VERSION 5.8 ;
BUSBITCHARS "[]" ;
DIVIDERCHAR "/" ;
UNITS
    DATABASE MICRONS 1000 ;
END UNITS

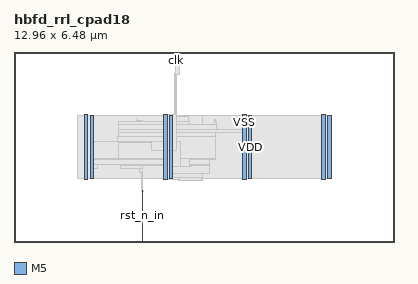
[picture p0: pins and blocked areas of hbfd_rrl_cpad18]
MACRO hbfd_rrl_cpad18
  FOREIGN hbfd_rrl_cpad18 0 0 ;
  CLASS BLOCK ;
  SIZE 12.96 BY 6.48 ;
  PIN clk
    DIRECTION INPUT ;
    USE SIGNAL ;
    PORT
      LAYER M5 ;
        RECT  5.52 6.396 5.544 6.48 ;
    END
  END clk
  PIN rst_n
    DIRECTION OUTPUT ;
    USE SIGNAL ;
    PORT
      LAYER M5 ;
        RECT  5.616 6.396 5.64 6.48 ;
    END
  END rst_n
  PIN rst_n_in
    DIRECTION INPUT ;
    USE SIGNAL ;
    PORT
      LAYER M5 ;
        RECT  4.368 0 4.392 0.084 ;
    END
    PORT
      LAYER M5 ;
        RECT  4.368 0.016 4.392 1.763 ;
    END
  END rst_n_in
  PIN VDD
    DIRECTION INOUT ;
    USE POWER ;
    PORT
      LAYER M5 ;
        RECT  10.692 2.151 10.812 4.329 ;
        RECT  7.992 2.151 8.112 4.329 ;
        RECT  5.292 2.151 5.412 4.329 ;
        RECT  2.592 2.151 2.712 4.329 ;
    END
  END VDD
  PIN VSS
    DIRECTION INOUT ;
    USE GROUND ;
    PORT
      LAYER M5 ;
        RECT  10.5 2.137 10.62 4.343 ;
        RECT  7.8 2.137 7.92 4.343 ;
        RECT  5.1 2.137 5.22 4.343 ;
        RECT  2.4 2.137 2.52 4.343 ;
    END
  END VSS
  # OT_OBS_CLOSED layer=M5 d_um=1.536 added=0
  OBS
    LAYER RVTN ;
     RECT  2.16 2.16 10.8 2.295 ;
     RECT  2.16 2.565 10.8 2.835 ;
     RECT  2.16 3.105 10.8 3.375 ;
     RECT  2.16 3.645 10.8 3.915 ;
     RECT  2.16 4.185 10.8 4.32 ;
    LAYER RVTP ;
     RECT  2.16 2.295 10.8 2.565 ;
     RECT  2.16 2.835 10.8 3.105 ;
     RECT  2.16 3.375 10.8 3.645 ;
     RECT  2.16 3.915 10.8 4.185 ;
    LAYER M1 ;
     RECT  2.16 2.151 10.8 4.329 ;
    LAYER M2 ;
     RECT  2.16 2.151 5.611 4.329 ;
     RECT  5.611 2.106 6.431 4.329 ;
     RECT  6.431 2.151 10.8 4.329 ;
     RECT  10.8 2.421 10.812 4.059 ;
    LAYER M3 ;
     RECT  5.616 2.101 5.634 2.143 ;
     RECT  5.115 2.143 5.634 2.191 ;
     RECT  6.408 2.101 6.426 2.191 ;
     RECT  5.115 2.191 6.426 2.335 ;
     RECT  4.356 1.723 4.374 2.371 ;
     RECT  2.415 2.143 2.505 2.413 ;
     RECT  7.815 2.143 7.905 2.413 ;
     RECT  10.515 2.143 10.605 2.413 ;
     RECT  2.415 2.413 2.697 2.497 ;
     RECT  4.284 2.371 4.374 2.497 ;
     RECT  3.636 2.497 4.374 2.605 ;
     RECT  5.115 2.335 6.678 2.605 ;
     RECT  2.415 2.497 2.862 2.641 ;
     RECT  3.636 2.605 6.678 2.641 ;
     RECT  2.415 2.641 6.678 2.803 ;
     RECT  2.415 2.803 6.858 2.861 ;
     RECT  3.528 2.861 6.858 3.605 ;
     RECT  3.564 3.605 6.858 3.721 ;
     RECT  7.815 2.413 8.097 3.721 ;
     RECT  3.564 3.721 8.097 3.839 ;
     RECT  3.564 3.839 6.894 4.019 ;
     RECT  2.415 2.861 2.697 4.067 ;
     RECT  7.815 3.839 8.097 4.067 ;
     RECT  10.515 2.413 10.797 4.067 ;
     RECT  3.564 4.019 5.994 4.109 ;
     RECT  6.84 4.019 6.894 4.109 ;
     RECT  4.176 4.109 4.374 4.145 ;
     RECT  4.176 4.145 4.194 4.181 ;
     RECT  6.84 4.109 6.858 4.181 ;
     RECT  5.115 4.109 5.958 4.289 ;
     RECT  2.415 4.067 2.505 4.337 ;
     RECT  5.115 4.289 5.49 4.337 ;
     RECT  7.815 4.067 7.905 4.337 ;
     RECT  10.515 4.067 10.605 4.337 ;
     RECT  5.472 4.337 5.49 5.741 ;
    LAYER M4 ;
     RECT  2.408 2.148 2.512 4.332 ;
     RECT  2.512 2.418 2.704 4.062 ;
     RECT  2.704 2.832 3.557 3.432 ;
     RECT  4.345 1.728 4.429 1.752 ;
     RECT  3.557 3.408 4.705 3.432 ;
     RECT  4.705 3.12 5.108 3.432 ;
     RECT  5.108 2.148 5.212 4.332 ;
     RECT  5.212 2.418 5.404 4.062 ;
     RECT  5.461 5.712 5.651 5.736 ;
     RECT  5.404 2.592 5.681 3.432 ;
     RECT  5.681 2.592 5.969 2.856 ;
     RECT  5.969 2.592 6.041 2.616 ;
     RECT  7.808 2.148 7.912 4.332 ;
     RECT  7.912 2.418 8.104 4.062 ;
     RECT  10.508 2.148 10.612 4.332 ;
     RECT  10.612 2.418 10.804 4.062 ;
    LAYER M5 ;
     RECT  2.4 2.137 2.52 2.151 ;
     RECT  5.1 2.137 5.22 2.151 ;
     RECT  7.8 2.137 7.92 2.151 ;
     RECT  10.5 2.137 10.62 2.151 ;
     RECT  5.1 2.151 5.412 3.109 ;
     RECT  2.4 2.151 2.712 4.329 ;
     RECT  7.8 2.151 8.112 4.329 ;
     RECT  10.5 2.151 10.812 4.329 ;
     RECT  2.4 4.329 2.52 4.343 ;
     RECT  5.1 3.109 5.544 4.343 ;
     RECT  7.8 4.329 7.92 4.343 ;
     RECT  10.5 4.329 10.62 4.343 ;
     RECT  5.52 4.343 5.544 5.701 ;
     RECT  5.52 5.701 5.64 6.396 ;
     RECT  5.544 6.396 5.616 6.416 ;
  END
END hbfd_rrl_cpad18
END LIBRARY
